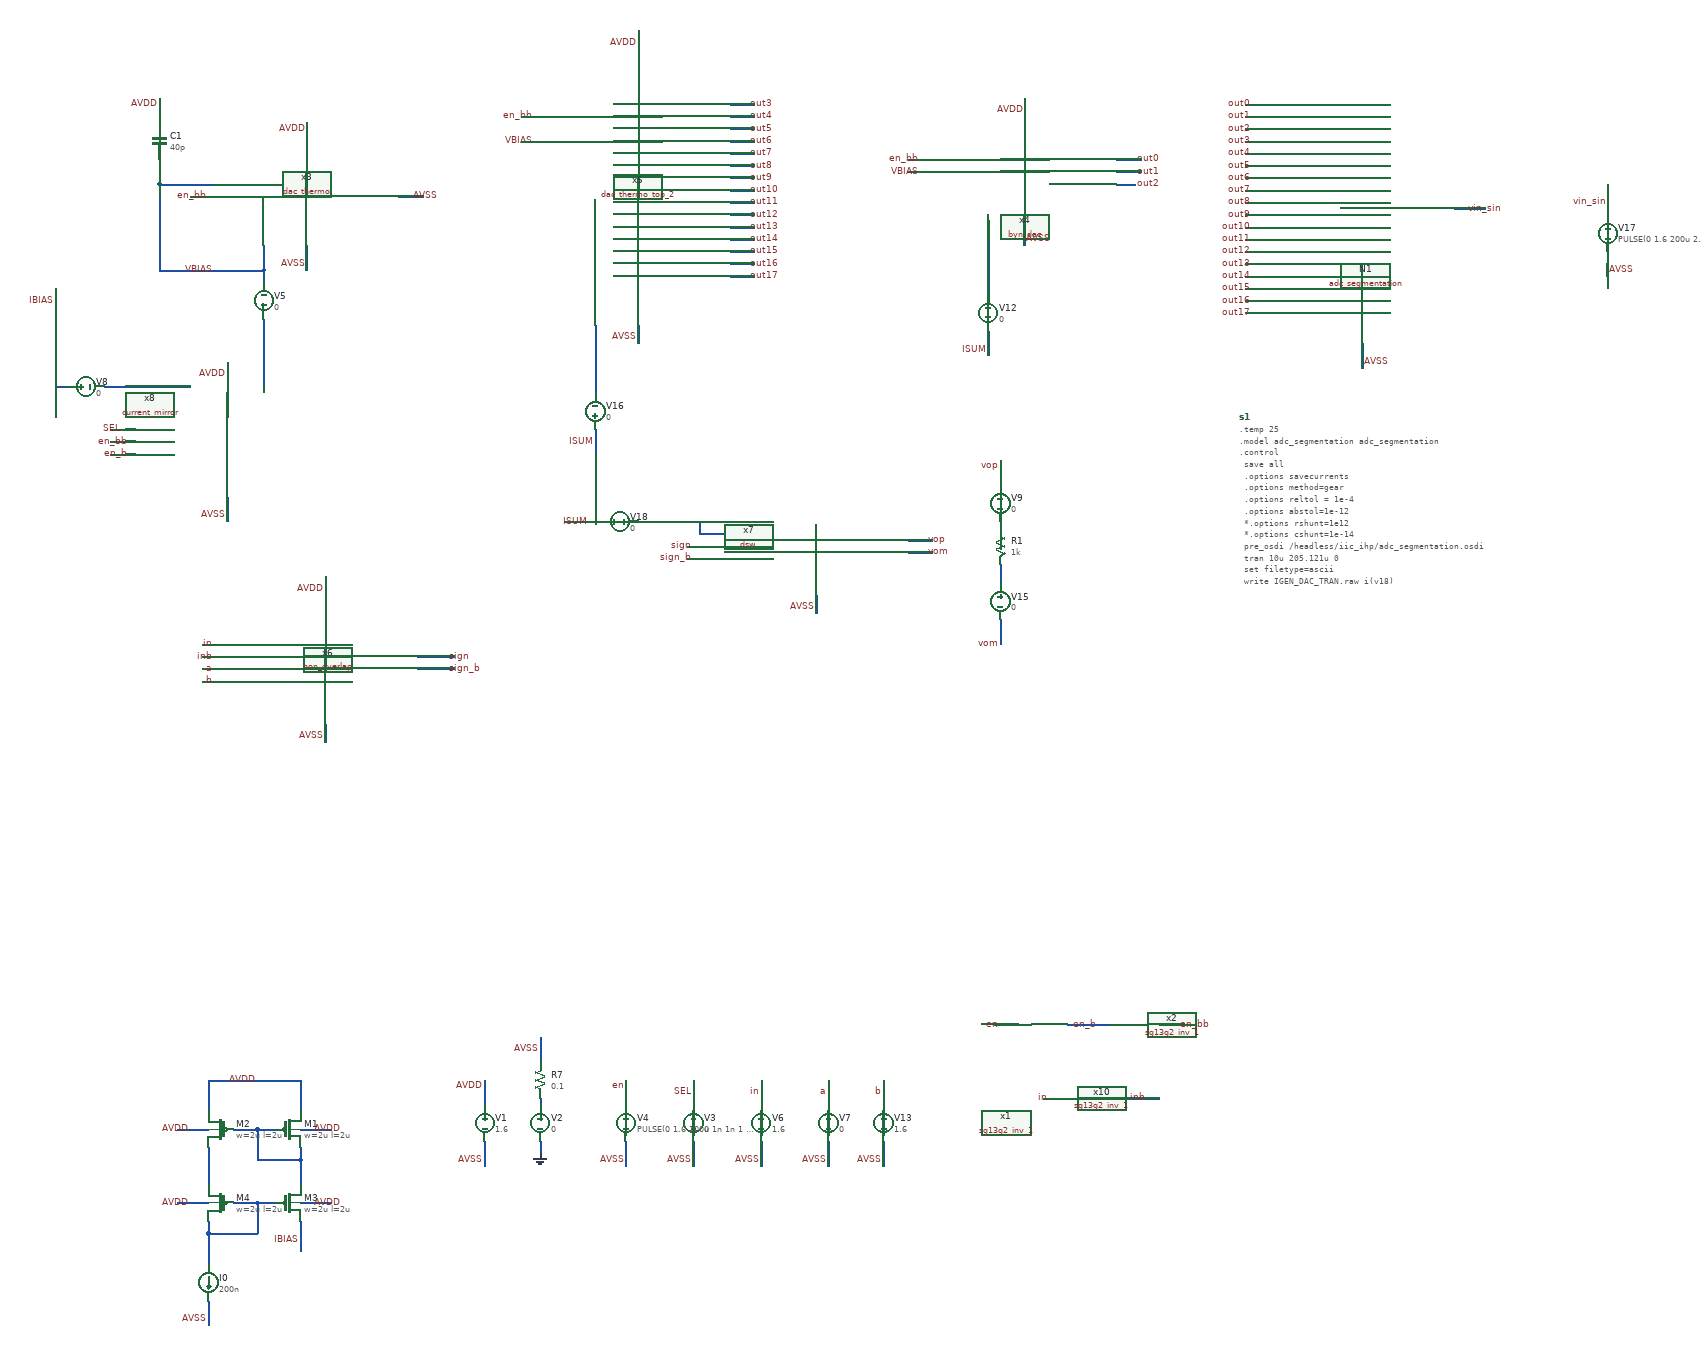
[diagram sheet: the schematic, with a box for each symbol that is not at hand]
v {xschem version=3.4.8RC file_version=1.3}
G {}
K {}
V {}
S {}
F {}
E {}
B 2 3330 -680 4130 -280 {flags=graph

ypos1=0
ypos2=2
divy=5
subdivy=4
unity=1
divx=5
subdivx=1
unitx=1
logx=0
logy=0
hilight_wave=0
autoload=0
x2=0.00020284052
x1=0.00020223393
y1=-2.1286944e-06
y2=-1.4524273e-07
rawfile=$netlist_dir/IGEN_DAC_TRAN.raw
dataset=0
color=4
node=i(v16)}
B 2 3330 -1140 4130 -740 {flags=graph

ypos1=0
ypos2=2
divy=5
subdivy=4
unity=1
divx=5
subdivx=1
unitx=1
logx=0
logy=0
hilight_wave=-1
autoload=0
x2=0.00020284052
x1=0.00020223393
y1=-7.2190263e-07
y2=4.1418525e-06
rawfile=$netlist_dir/IGEN_DAC_TRAN.raw
dataset=0
color=6
node=i(v18)}
B 2 3290 -1750 4090 -1350 {flags=graph

ypos1=0
ypos2=2
divy=5
subdivy=4
unity=1
divx=5
subdivx=1
unitx=1
logx=0
logy=0
hilight_wave=-1
autoload=0
x2=0.00020284052
x1=0.00020223393
y1=-2.074257e-07
y2=2.3194213e-08
rawfile=$netlist_dir/IGEN_DAC_TRAN.raw
dataset=0
color=4
node=i(v12)}
B 2 4295 -1750 5095 -1350 {flags=graph

ypos1=0
ypos2=2
divy=5
subdivy=4
unity=1
divx=5
subdivx=1
unitx=1
logx=0
logy=0
hilight_wave=-1
autoload=1
x2=0.00020284052
x1=0.00020223393
y1=2.72
y2=4.42
rawfile=$netlist_dir/IGEN_DAC_TRAN.raw
dataset=0
color="4 7 12"
node="out0
out1
out2"}
B 2 4305 -1135 5105 -735 {flags=graph

ypos1=0
ypos2=2
divy=5
subdivy=4
unity=1
divx=5
subdivx=1
unitx=1
logx=0
logy=0
hilight_wave=-1
autoload=1
x2=0.00020284052
x1=0.00020223393
y1=-0.050608856
y2=1.649391
rawfile=$netlist_dir/IGEN_DAC_TRAN.raw
dataset=0
color="1 4 5 6 7 8 9 10 11 12 13 14 15 16 17"
node="out17
out16
out15
out14
out13
out12
out11
out10
out9
out8
out7
out6
out5
out4
out3"}
B 2 4305 -665 5105 -265 {flags=graph

ypos1=0
ypos2=2
divy=5
subdivy=4
unity=1
divx=5
subdivx=1
unitx=1
logx=0
logy=0
hilight_wave=-1
autoload=1
x2=0.00020284052
x1=0.00020223393
y1=-1.9e-13
y2=1.7
rawfile=$netlist_dir/IGEN_DAC_TRAN.raw
dataset=0
color=4
node=vin_sin}
B 2 4055 125 4855 525 {flags=graph

ypos1=0
ypos2=2
divy=5
subdivy=4
unity=1
divx=5
subdivx=1
unitx=1
logx=0
logy=0
hilight_wave=-1
autoload=1
x2=0.00020284052
x1=0.00020223393
y1=2.1141035e-07
y2=2.6026014e-07
rawfile=$netlist_dir/IGEN_DAC_TRAN.raw
dataset=0
color=4
node=i(v.x5.x1.v5)}
B 2 4905 125 5705 525 {flags=graph

ypos1=0
ypos2=2
divy=5
subdivy=4
unity=1
divx=5
subdivx=1
unitx=1
logx=0
logy=0
hilight_wave=-1
autoload=1
x2=0.00020284052
x1=0.00020223393
y1=-1.8851069e-08
y2=3.9768677e-08
rawfile=$netlist_dir/IGEN_DAC_TRAN.raw
dataset=0
color=4
node=i(v.x4.x1.v5)}
B 2 5795 115 6595 515 {flags=graph

ypos1=0
ypos2=2
divy=5
subdivy=4
unity=1
divx=5
subdivx=1
unitx=1
logx=0
logy=0
hilight_wave=-1
autoload=1
x2=0.00020284052
x1=0.00020223393
y1=-1.8851069e-08
y2=3.9768677e-08
rawfile=$netlist_dir/IGEN_DAC_TRAN.raw
dataset=0
color="4 7"
node="i(v.x4.x2.v5)
i(v.x4.x3.v5)"}
B 2 4045 585 4845 985 {flags=graph

ypos1=0
ypos2=2
divy=5
subdivy=4
unity=1
divx=5
subdivx=1
unitx=1
logx=0
logy=0
hilight_wave=-1
autoload=1
x2=0.00020284052
x1=0.00020223393
y1=2.0056422e-07
y2=2.7090792e-07
rawfile=$netlist_dir/IGEN_DAC_TRAN.raw
dataset=0
color=4
node=i(v.x5.x2.v5)}
B 2 4935 620 5735 1020 {flags=graph

ypos1=0
ypos2=2
divy=5
subdivy=4
unity=1
divx=5
subdivx=1
unitx=1
logx=0
logy=0
hilight_wave=-1
autoload=1
x2=0.00020284052
x1=0.00020223393
y1=5.5511151e-17
y2=1.7
rawfile=$netlist_dir/IGEN_DAC_TRAN.raw
dataset=0
color="4 7 12"
node="out0
out1
out2"}
B 2 5260 -1740 6060 -1340 {flags=graph

ypos1=0
ypos2=2
divy=5
subdivy=4
unity=1
divx=5
subdivx=1
unitx=1
logx=0
logy=0
hilight_wave=0
autoload=0
x2=0.00020284052
x1=0.00020223393
y1=1.2802536
y2=1.323824
rawfile=$netlist_dir/IGEN_DAC_TRAN.raw
dataset=0
color=4
node=vbias}
B 2 4860 -3330 5660 -2930 {flags=graph

ypos1=0
ypos2=2
divy=5
subdivy=4
unity=1
divx=5
subdivx=1
unitx=1
logx=0
logy=0
hilight_wave=-1
autoload=0
x2=0.00020284052
x1=0.00020223393
y1=-2.4077769e-07
y2=2.8581253e-08
rawfile=$netlist_dir/IGEN_DAC_TRAN.raw
dataset=0
color=4
node=i(v12)}
B 2 4850 -2880 5650 -2480 {flags=graph

ypos1=0
ypos2=2
divy=5
subdivy=4
unity=1
divx=5
subdivx=1
unitx=1
logx=0
logy=0
hilight_wave=0
autoload=0
x2=0.00020284052
x1=0.00020223393
y1=-4.3876253e-06
y2=-2.4041737e-06
rawfile=$netlist_dir/IGEN_DAC_TRAN.raw
dataset=0
color=4
node=i(v16)}
B 2 5955 -3330 6755 -2930 {flags=graph

ypos1=0
ypos2=2
divy=5
subdivy=4
unity=1
divx=5
subdivx=1
unitx=1
logx=0
logy=0
hilight_wave=-1
autoload=1
x2=0.00020284052
x1=0.00020223393
y1=0
y2=1.7
rawfile=$netlist_dir/IGEN_DAC_TRAN.raw
dataset=0
color="4 7 12"
node="out0
out1
out2"}
B 2 5955 -2855 6755 -2455 {flags=graph

ypos1=0
ypos2=2
divy=5
subdivy=4
unity=1
divx=5
subdivx=1
unitx=1
logx=0
logy=0
hilight_wave=-1
autoload=1
x2=0.00020284052
x1=0.00020223393
y1=-0.050608796
y2=1.649391
rawfile=$netlist_dir/IGEN_DAC_TRAN.raw
dataset=0
color="1 4 5 6 7 8 9 10 11 12 13 14 15 16 17"
node="out17
out16
out15
out14
out13
out12
out11
out10
out9
out8
out7
out6
out5
out4
out3"}
N 190 -620 190 -580 {lab=AVDD}
N 320 -1010 320 -970 {lab=AVDD}
N 190 -400 190 -360 {lab=AVSS}
N 0 -510 40 -510 {lab=SEL}
N 0 -490 40 -490 {lab=en_bb}
N 0 -470 40 -470 {lab=en_b}
N 130 -890 170 -890 {lab=en_bb}
N 470 -890 510 -890 {lab=AVSS}
N 320 -810 320 -770 {lab=AVSS}
N 860 -1160 860 -1120 {lab=AVDD}
N 670 -980 710 -980 {lab=VBIAS}
N 670 -1020 710 -1020 {lab=en_bb}
N 860 -680 860 -650 {lab=AVSS}
N 790 -510 790 -470 {lab=ISUM}
N 160 910 160 950 {lab=AVSS}
N 610 550 610 590 {lab=AVDD}
N 610 650 610 690 {lab=AVSS}
N 700 650 700 670 {lab=GND}
N 700 480 700 520 {lab=AVSS}
N 840 550 840 590 {lab=en}
N 840 650 840 690 {lab=AVSS}
N 1440 460 1480 460 {lab=en}
N 1560 460 1630 460 {lab=en_b}
N 1710 460 1750 460 {lab=en_bb}
N 80 -910 170 -910 {lab=VBIAS}
N 80 -910 80 -770 {lab=VBIAS}
N 80 -770 250 -770 {lab=VBIAS}
N 250 -810 250 -770 {lab=VBIAS}
N 950 550 950 590 {lab=SEL}
N 950 650 950 690 {lab=AVSS}
N 1060 550 1060 590 {lab=in}
N 1060 650 1060 690 {lab=AVSS}
N 1520 580 1560 580 {lab=in}
N 1640 580 1710 580 {lab=inb}
N 240 630 270 630 {lab=#net1}
N 160 660 160 720 {lab=#net2}
N 240 750 270 750 {lab=#net3}
N 310 680 310 720 {lab=#net1}
N 240 750 240 800 {lab=#net3}
N 200 750 240 750 {lab=#net3}
N 160 800 240 800 {lab=#net3}
N 160 780 160 800 {lab=#net3}
N 240 630 240 680 {lab=#net1}
N 200 630 240 630 {lab=#net1}
N 240 680 310 680 {lab=#net1}
N 310 660 310 680 {lab=#net1}
N 160 550 160 600 {lab=AVDD}
N 160 550 310 550 {lab=AVDD}
N 310 550 310 600 {lab=AVDD}
N 310 780 310 830 {lab=IBIAS}
N 110 630 160 630 {lab=AVDD}
N 110 750 160 750 {lab=AVDD}
N 310 750 360 750 {lab=AVDD}
N 310 630 360 630 {lab=AVDD}
N 160 800 160 850 {lab=#net3}
N 790 -680 790 -570 {lab=#net4}
N 1640 -930 1680 -930 {lab=out1}
N 1640 -950 1680 -950 {lab=out0}
N 1640 -910 1670 -910 {lab=out2}
N 2040 -650 2040 -610 {lab=AVSS}
N 1850 -1040 1890 -1040 {lab=out0}
N 1850 -1020 1890 -1020 {lab=out1}
N 1850 -1000 1890 -1000 {lab=out2}
N 1850 -980 1890 -980 {lab=out3}
N 1850 -960 1890 -960 {lab=out4}
N 1850 -940 1890 -940 {lab=out5}
N 1850 -920 1890 -920 {lab=out6}
N 1850 -900 1890 -900 {lab=out7}
N 1850 -880 1890 -880 {lab=out8}
N 1850 -860 1890 -860 {lab=out9}
N 1850 -840 1890 -840 {lab=out10}
N 1850 -820 1890 -820 {lab=out11}
N 1850 -800 1890 -800 {lab=out12}
N 1850 -780 1890 -780 {lab=out13}
N 1850 -760 1890 -760 {lab=out14}
N 1850 -740 1890 -740 {lab=out15}
N 1850 -720 1890 -720 {lab=out16}
N 1850 -700 1890 -700 {lab=out17}
N 2190 -870 2240 -870 {lab=vin_sin}
N 2440 -800 2440 -760 {lab=AVSS}
N 2440 -910 2440 -860 {lab=vin_sin}
N 1010 -1040 1050 -1040 {lab=out3}
N 1010 -1020 1050 -1020 {lab=out4}
N 1010 -1000 1050 -1000 {lab=out5}
N 1010 -980 1050 -980 {lab=out6}
N 1010 -960 1050 -960 {lab=out7}
N 1010 -940 1050 -940 {lab=out8}
N 1010 -920 1050 -920 {lab=out9}
N 1010 -900 1050 -900 {lab=out10}
N 1010 -880 1050 -880 {lab=out11}
N 1010 -860 1050 -860 {lab=out12}
N 1010 -840 1050 -840 {lab=out13}
N 1010 -820 1050 -820 {lab=out14}
N 1010 -800 1050 -800 {lab=out15}
N 1010 -780 1050 -780 {lab=out16}
N 1010 -760 1050 -760 {lab=out17}
N 500 -140 560 -140 {lab=sign}
N 500 -120 560 -120 {lab=sign_b}
N 350 -30 350 0 {lab=AVSS}
N 350 -270 350 -230 {lab=AVDD}
N 150 -160 200 -160 {lab=in}
N 150 -140 200 -140 {lab=inb}
N 150 -120 200 -120 {lab=a}
N 150 -100 200 -100 {lab=b}
N 1170 550 1170 590 {lab=a}
N 1170 650 1170 690 {lab=AVSS}
N 1260 550 1260 590 {lab=b}
N 1260 650 1260 690 {lab=AVSS}
N 1490 -850 1490 -810 {lab=AVSS}
N 1490 -1050 1490 -1010 {lab=AVDD}
N 1300 -930 1340 -930 {lab=VBIAS}
N 1300 -950 1340 -950 {lab=en_bb}
N -10 -580 130 -580 {lab=#net5}
N -90 -580 -70 -580 {lab=IBIAS}
N 1430 -670 1430 -630 {lab=ISUM}
N -90 -740 -90 -580 {lab=IBIAS}
N 700 580 700 590 {lab=#net6}
N 250 -770 250 -750 {lab=VBIAS}
N 250 -690 250 -580 {lab=#net7}
N 940 -320 1000 -320 {lab=sign}
N 940 -300 1000 -300 {lab=sign_b}
N 1300 -330 1340 -330 {lab=vop}
N 1300 -310 1340 -310 {lab=vom}
N 1150 -240 1150 -210 {lab=AVSS}
N 960 -340 1000 -340 {lab=#net8}
N 1450 -460 1450 -420 {lab=vop}
N 1450 -200 1450 -160 {lab=vom}
N 1450 -290 1450 -260 {lab=#net9}
N 1450 -360 1450 -350 {lab=#net10}
N 740 -360 800 -360 {lab=ISUM}
N 860 -360 960 -360 {lab=#net8}
N 960 -360 960 -340 {lab=#net8}
N 80 -950 80 -910 {lab=VBIAS}
N 80 -1050 80 -1010 {lab=AVDD}
N 1430 -850 1430 -730 {lab=#net11}
C {dac_thermo.sym} 320 -890 0 0 {name=x3}
C {current_mirror.sym} 190 -490 0 0 {name=x8}
C {lab_wire.sym} 190 -600 0 0 {name=p1 sig_type=std_logic lab=AVDD}
C {lab_wire.sym} 170 -770 0 0 {name=p2 sig_type=std_logic lab=VBIAS}
C {lab_wire.sym} 20 -510 0 0 {name=p4 sig_type=std_logic lab=SEL}
C {lab_wire.sym} 30 -490 0 0 {name=p6 sig_type=std_logic lab=en_bb}
C {lab_wire.sym} 30 -470 0 0 {name=p7 sig_type=std_logic lab=en_b}
C {lab_wire.sym} 190 -370 0 0 {name=p8 sig_type=std_logic lab=AVSS}
C {lab_wire.sym} 320 -780 0 0 {name=p9 sig_type=std_logic lab=AVSS}
C {lab_wire.sym} 320 -1000 0 0 {name=p14 sig_type=std_logic lab=AVDD}
C {lab_wire.sym} 860 -1140 0 0 {name=p15 sig_type=std_logic lab=AVDD}
C {lab_wire.sym} 160 -890 0 0 {name=p19 sig_type=std_logic lab=en_bb}
C {lab_wire.sym} 690 -980 0 0 {name=p20 sig_type=std_logic lab=VBIAS}
C {lab_wire.sym} 690 -1020 0 0 {name=p21 sig_type=std_logic lab=en_bb}
C {lab_wire.sym} 490 -890 0 1 {name=p28 sig_type=std_logic lab=AVSS}
C {isource.sym} 160 880 0 0 {name=I0 value=200n}
C {vsource.sym} 610 620 0 0 {name=V1 value=1.6 savecurrent=false}
C {lab_wire.sym} 610 680 0 0 {name=p40 sig_type=std_logic lab=AVSS}
C {gnd.sym} 700 670 0 0 {name=l1 lab=GND}
C {vsource.sym} 700 620 0 0 {name=V2 value=0 savecurrent=false}
C {lab_wire.sym} 700 500 0 0 {name=p41 sig_type=std_logic lab=AVSS}
C {vsource.sym} 950 620 0 0 {name=V3 value=0 savecurrent=false}
C {lab_wire.sym} 840 560 0 0 {name=p42 sig_type=std_logic lab=en}
C {lab_wire.sym} 840 680 0 0 {name=p43 sig_type=std_logic lab=AVSS}
C {sg13g2_stdcells/sg13g2_inv_1.sym} 1520 460 0 0 {name=x1 VDD=AVDD VSS=AVSS prefix=sg13g2_ }
C {lab_wire.sym} 1450 460 0 0 {name=p44 sig_type=std_logic lab=en}
C {sg13g2_stdcells/sg13g2_inv_1.sym} 1670 460 0 0 {name=x2 VDD=AVDD VSS=AVSS prefix=sg13g2_ }
C {lab_wire.sym} 1610 460 0 0 {name=p45 sig_type=std_logic lab=en_b}
C {lab_wire.sym} -90 -720 0 0 {name=p3 sig_type=std_logic lab=IBIAS}
C {lab_wire.sym} 950 680 0 0 {name=p48 sig_type=std_logic lab=AVSS}
C {lab_wire.sym} 950 570 0 0 {name=p5 sig_type=std_logic lab=SEL}
C {code_shown.sym} 1840 -530 0 0 {name=s1 only_toplevel=false value="
.temp 25
.model adc_segmentation adc_segmentation
.control
 save all
 .options savecurrents
 .options method=gear
 .options reltol = 1e-4
 .options abstol=1e-12
 *.options rshunt=1e12
 *.options cshunt=1e-14
 pre_osdi /headless/iic_ihp/adc_segmentation.osdi
 tran 10u 205.121u 0 
 set filetype=ascii
 write IGEN_DAC_TRAN.raw i(v18) 
 write IGEN_DAC_TRAN.txt  
 *dc V17 0 1.6 0.01
 *dc V1 1.2 1.2 0.01
 *set filetype=ascii
 *write IGEN_DAC_DC.raw
 *plot v(VBIAS)
 *plot i(V7)
 *plot i(V8)
 *plot i(V9)
 *plot @i0[current]
.endc
.include /foss/pdks/ihp-sg13g2/libs.ref/sg13g2_stdcell/spice/sg13g2_stdcell.spice
.lib /foss/pdks/ihp-sg13g2/libs.tech/ngspice/models/cornerMOSlv.lib mos_tt
.lib /foss/pdks/ihp-sg13g2/libs.tech/ngspice/models/cornerCAP.lib cap_typ
.lib /foss/pdks/ihp-sg13g2/libs.tech/ngspice/models/cornerRES.lib res_typ
"}
C {lab_wire.sym} 1740 460 0 1 {name=p50 sig_type=std_logic lab=en_bb}
C {vsource.sym} 1060 620 0 0 {name=V6 value=1.6 savecurrent=false}
C {lab_wire.sym} 1060 680 0 0 {name=p55 sig_type=std_logic lab=AVSS}
C {lab_wire.sym} 1060 570 0 0 {name=p56 sig_type=std_logic lab=in}
C {sg13g2_stdcells/sg13g2_inv_1.sym} 1600 580 0 0 {name=x10 VDD=AVDD VSS=AVSS prefix=sg13g2_ }
C {lab_wire.sym} 1530 580 0 0 {name=p57 sig_type=std_logic lab=in}
C {lab_wire.sym} 1690 580 0 0 {name=p58 sig_type=std_logic lab=inb}
C {lab_wire.sym} 610 560 0 0 {name=p39 sig_type=std_logic lab=AVDD}
C {sg13g2_pr/sg13_lv_pmos.sym} 290 630 0 0 {name=M1
l=2u
w=2u
ng=1
m=2
model=sg13_lv_pmos
spiceprefix=X
}
C {sg13g2_pr/sg13_lv_pmos.sym} 180 630 0 1 {name=M2
l=2u
w=2u
ng=1
m=2
model=sg13_lv_pmos
spiceprefix=X
}
C {sg13g2_pr/sg13_lv_pmos.sym} 290 750 0 0 {name=M3
l=2u
w=2u
ng=1
m=2
model=sg13_lv_pmos
spiceprefix=X
}
C {sg13g2_pr/sg13_lv_pmos.sym} 180 750 0 1 {name=M4
l=2u
w=2u
ng=1
m=21
model=sg13_lv_pmos
spiceprefix=X
}
C {lab_wire.sym} 240 550 0 0 {name=p61 sig_type=std_logic lab=AVDD}
C {lab_wire.sym} 130 630 0 0 {name=p62 sig_type=std_logic lab=AVDD}
C {lab_wire.sym} 130 750 0 0 {name=p63 sig_type=std_logic lab=AVDD}
C {lab_wire.sym} 330 750 0 1 {name=p64 sig_type=std_logic lab=AVDD}
C {lab_wire.sym} 330 630 0 1 {name=p65 sig_type=std_logic lab=AVDD}
C {lab_wire.sym} 160 940 0 0 {name=p37 sig_type=std_logic lab=AVSS}
C {lab_wire.sym} 310 810 0 0 {name=p38 sig_type=std_logic lab=IBIAS}
C {vsource.sym} 790 -540 2 0 {name=V16 value=0 savecurrent=false}
C {lab_wire.sym} 860 -660 1 1 {name=p29 sig_type=std_logic lab=AVSS}
C {lab_wire.sym} 790 -490 0 0 {name=p18 sig_type=std_logic lab=ISUM}
C {adc_segmentation.sym} 2040 -870 0 1 {name=N1 model=adc_segmentation}
C {lab_wire.sym} 2040 -620 0 1 {name=p60 sig_type=std_logic lab=AVSS}
C {lab_wire.sym} 1860 -1040 0 0 {name=p69 sig_type=std_logic lab=out0}
C {lab_wire.sym} 1860 -1020 0 0 {name=p70 sig_type=std_logic lab=out1}
C {lab_wire.sym} 1860 -1000 0 0 {name=p73 sig_type=std_logic lab=out2}
C {lab_wire.sym} 1860 -980 0 0 {name=p74 sig_type=std_logic lab=out3}
C {lab_wire.sym} 1860 -960 0 0 {name=p75 sig_type=std_logic lab=out4}
C {lab_wire.sym} 1860 -940 0 0 {name=p76 sig_type=std_logic lab=out5}
C {lab_wire.sym} 1860 -920 0 0 {name=p77 sig_type=std_logic lab=out6}
C {lab_wire.sym} 1860 -900 0 0 {name=p78 sig_type=std_logic lab=out7}
C {lab_wire.sym} 1860 -880 0 0 {name=p79 sig_type=std_logic lab=out8}
C {lab_wire.sym} 1860 -860 0 0 {name=p80 sig_type=std_logic lab=out9}
C {lab_wire.sym} 1860 -840 0 0 {name=p81 sig_type=std_logic lab=out10}
C {lab_wire.sym} 1860 -820 0 0 {name=p82 sig_type=std_logic lab=out11}
C {lab_wire.sym} 1860 -800 0 0 {name=p83 sig_type=std_logic lab=out12}
C {lab_wire.sym} 1860 -780 0 0 {name=p84 sig_type=std_logic lab=out13}
C {lab_wire.sym} 1860 -760 0 0 {name=p85 sig_type=std_logic lab=out14}
C {lab_wire.sym} 1860 -740 0 0 {name=p86 sig_type=std_logic lab=out15}
C {lab_wire.sym} 1860 -720 0 0 {name=p87 sig_type=std_logic lab=out16}
C {lab_wire.sym} 1860 -700 0 0 {name=p88 sig_type=std_logic lab=out17}
C {lab_wire.sym} 2210 -870 0 1 {name=p89 sig_type=std_logic lab=vin_sin}
C {lab_wire.sym} 2440 -770 0 1 {name=p90 sig_type=std_logic lab=AVSS}
C {lab_wire.sym} 2440 -880 3 1 {name=p91 sig_type=std_logic lab=vin_sin}
C {lab_wire.sym} 1670 -950 0 1 {name=p13 sig_type=std_logic lab=out0}
C {lab_wire.sym} 1670 -930 0 1 {name=p71 sig_type=std_logic lab=out1}
C {lab_wire.sym} 1670 -910 0 1 {name=p72 sig_type=std_logic lab=out2}
C {lab_wire.sym} 1040 -1040 0 1 {name=p92 sig_type=std_logic lab=out3}
C {lab_wire.sym} 1040 -1020 0 1 {name=p93 sig_type=std_logic lab=out4}
C {lab_wire.sym} 1040 -1000 0 1 {name=p94 sig_type=std_logic lab=out5}
C {lab_wire.sym} 1040 -980 0 1 {name=p95 sig_type=std_logic lab=out6}
C {lab_wire.sym} 1040 -960 0 1 {name=p96 sig_type=std_logic lab=out7}
C {lab_wire.sym} 1040 -940 0 1 {name=p97 sig_type=std_logic lab=out8}
C {lab_wire.sym} 1040 -920 0 1 {name=p98 sig_type=std_logic lab=out9}
C {lab_wire.sym} 1040 -900 0 1 {name=p99 sig_type=std_logic lab=out10}
C {lab_wire.sym} 1040 -880 0 1 {name=p100 sig_type=std_logic lab=out11}
C {lab_wire.sym} 1040 -860 0 1 {name=p101 sig_type=std_logic lab=out12}
C {lab_wire.sym} 1040 -840 0 1 {name=p102 sig_type=std_logic lab=out13}
C {lab_wire.sym} 1040 -820 0 1 {name=p103 sig_type=std_logic lab=out14}
C {lab_wire.sym} 1040 -800 0 1 {name=p104 sig_type=std_logic lab=out15}
C {lab_wire.sym} 1040 -780 0 1 {name=p105 sig_type=std_logic lab=out16}
C {lab_wire.sym} 1040 -760 0 1 {name=p106 sig_type=std_logic lab=out17}
C {non_overlap.sym} 350 -130 0 0 {name=x6}
C {lab_wire.sym} 550 -140 0 1 {name=p10 sig_type=std_logic lab=sign}
C {lab_wire.sym} 550 -120 0 1 {name=p12 sig_type=std_logic lab=sign_b}
C {lab_wire.sym} 350 -10 0 0 {name=p16 sig_type=std_logic lab=AVSS}
C {lab_wire.sym} 350 -250 0 0 {name=p17 sig_type=std_logic lab=AVDD}
C {lab_wire.sym} 170 -140 0 0 {name=p24 sig_type=std_logic lab=inb}
C {lab_wire.sym} 170 -160 0 0 {name=p25 sig_type=std_logic lab=in}
C {vsource.sym} 1170 620 0 0 {name=V7 value=0 savecurrent=false}
C {lab_wire.sym} 1170 680 0 0 {name=p26 sig_type=std_logic lab=AVSS}
C {lab_wire.sym} 1170 570 0 0 {name=p27 sig_type=std_logic lab=a}
C {vsource.sym} 1260 620 0 0 {name=V13 value=1.6 savecurrent=false}
C {lab_wire.sym} 1260 680 0 0 {name=p30 sig_type=std_logic lab=AVSS}
C {lab_wire.sym} 1260 570 0 0 {name=p31 sig_type=std_logic lab=b}
C {lab_wire.sym} 170 -120 0 0 {name=p33 sig_type=std_logic lab=a}
C {lab_wire.sym} 170 -100 0 0 {name=p34 sig_type=std_logic lab=b}
C {vsource.sym} 2440 -830 0 0 {name=V17 value="PULSE(0 1.6 200u 2.56u 2.56u 1n 205.121u)" savecurrent=false}
C {byn_dac.sym} 1490 -930 0 0 {name=x4}
C {lab_wire.sym} 1490 -820 0 1 {name=p11 sig_type=std_logic lab=AVSS}
C {lab_wire.sym} 1490 -1030 0 0 {name=p22 sig_type=std_logic lab=AVDD}
C {lab_wire.sym} 1320 -930 0 0 {name=p23 sig_type=std_logic lab=VBIAS}
C {lab_wire.sym} 1320 -950 0 0 {name=p32 sig_type=std_logic lab=en_bb}
C {vsource.sym} 1430 -700 2 0 {name=V12 value=0 savecurrent=false}
C {lab_wire.sym} 1430 -640 0 0 {name=p49 sig_type=std_logic lab=ISUM}
C {vsource.sym} 840 620 0 0 {name=V4 value="PULSE(0 1.6 100u 1n 1n 1 2)" savecurrent=false}
C {res.sym} 700 550 2 0 {name=R7
value=0.1
footprint=1206
device=resistor
m=1}
C {vsource.sym} 250 -720 2 0 {name=V5 value=0 savecurrent=false}
C {vsource.sym} -40 -580 3 0 {name=V8 value=0 savecurrent=false}
C {lab_wire.sym} 1330 -330 0 1 {name=p35 sig_type=std_logic lab=vop}
C {dsw.sym} 1150 -320 0 0 {name=x7}
C {lab_wire.sym} 1330 -310 0 1 {name=p36 sig_type=std_logic lab=vom}
C {lab_wire.sym} 1150 -220 0 0 {name=p47 sig_type=std_logic lab=AVSS}
C {lab_wire.sym} 950 -320 0 0 {name=p68 sig_type=std_logic lab=sign}
C {lab_wire.sym} 950 -300 0 0 {name=p107 sig_type=std_logic lab=sign_b}
C {lab_wire.sym} 1450 -450 3 1 {name=p108 sig_type=std_logic lab=vop}
C {lab_wire.sym} 1450 -160 3 1 {name=p109 sig_type=std_logic lab=vom}
C {vsource.sym} 1450 -390 0 0 {name=V9 value=0 savecurrent=false}
C {vsource.sym} 1450 -230 0 0 {name=V15 value=0 savecurrent=false}
C {lab_wire.sym} 780 -360 0 0 {name=p110 sig_type=std_logic lab=ISUM}
C {vsource.sym} 830 -360 3 0 {name=V18 value=0 savecurrent=false}
C {res.sym} 1450 -320 0 0 {name=R1
value=1k
footprint=1206
device=resistor
m=1}
C {capa.sym} 80 -980 0 0 {name=C1
m=1
value=40p
footprint=1206
device="ceramic capacitor"}
C {lab_wire.sym} 80 -1040 0 0 {name=p111 sig_type=std_logic lab=AVDD}
C {dac_thermo_top_2.sym} 860 -910 0 0 {name=x5}
